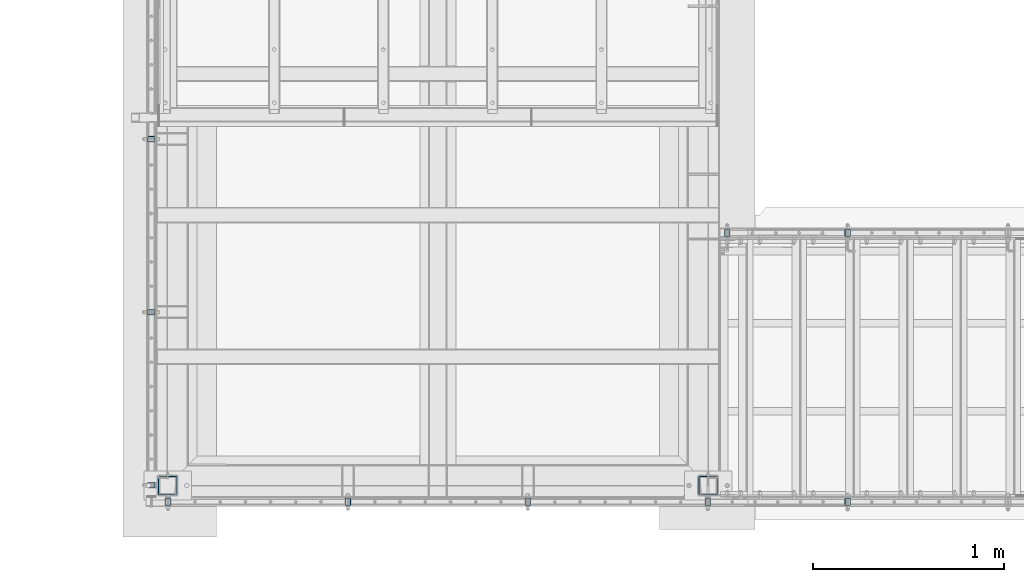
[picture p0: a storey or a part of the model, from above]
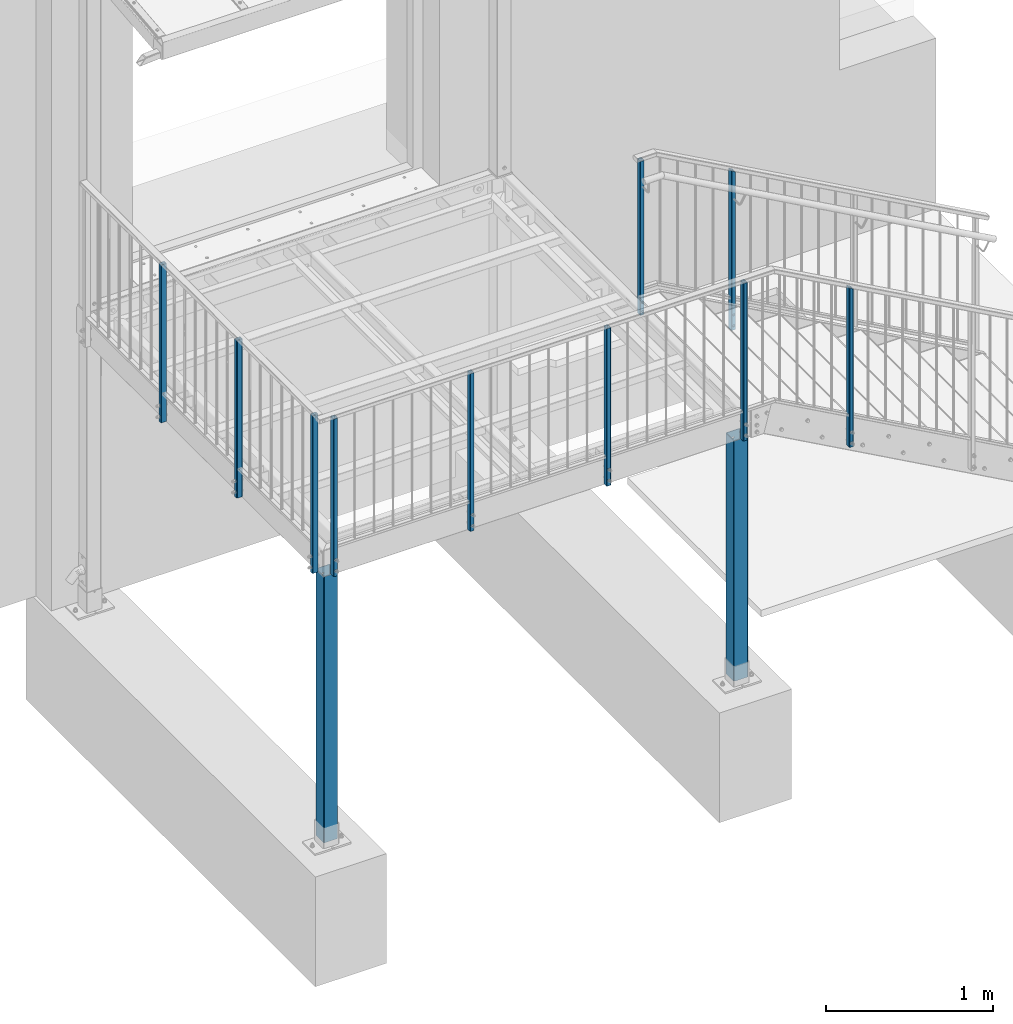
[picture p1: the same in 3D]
Properties of the parts of a building model (IFC2X3)

# File
Description: ViewDefinition[CoordinationView_V2.0]
File name: Einzelbalkon mit Zugangstreppe Bonn_ifc2x3.ifc
Time: 2026-07-13T14:27:18
Written by: IFC Toolkit 2.0.26.0
Made in: Advance Steel 2024

# IfcBuildingStorey, Default Storey
In: Struktur 1
Elevation: 0 mm

# IfcBeam: - (100)
In: Default Storey
Name | Description = Section | Material | SectionFamily
- | Q100X4 | S235JR | RHS_Sections_square_c nach DIN
- | Rinnenprofil 130x5 | S235JR | Usr Rinnenprofile | Pset_BeamCommon - Reference: 26; Span: 2920 mm; Slope: 0 deg; IsExternal: no; LoadBearing: no
9 x - | FL75X6 | S235JR | Flat nach DIN
6 x - | Gummistreifen 60x3 | Gummi | Usr Auflagergummi schwarz | Pset_BeamCommon - Reference: 5; Span: 200 mm; Slope: 0 deg; IsExternal: no; LoadBearing: no
6 x - | L 200x100x10 | Alu | Usr Auflagerwinkel Alu | Pset_BeamCommon - Reference: 10; Span: 60 mm; Slope: 0 deg; IsExternal: no; LoadBearing: no
3 x - | RHS80X60X4 | S235JR | RHS_Sections_rectang_c nach DIN
27 x - | FL40X5 | S235JR | Flat nach DIN
- | L60X40X5 | S235JR | Angle_uneq DIN18800-1 | Pset_BeamCommon - Reference: 19; Span: 1340 mm; Slope: 0 deg; IsExternal: no; LoadBearing: no
2 x - | C-Profil 217x30x4 | S235JR | Usr Treppenwangen trefor W
8 x - | R30X20X2 | S235JR | RHS_Sections_rectang_c nach DIN
- | R50X30X3 | S235JR | RHS_Sections_rectang_c nach DIN | Pset_BeamCommon - Reference: 23; Span: 3139.58 mm; Slope: 0 deg; IsExternal: no; LoadBearing: no
- | R50X30X3 | S235JR | RHS_Sections_rectang_c nach DIN
19 x - | FL80X6 | S235JR | Flat nach DIN
8 x - |  | S235JR | Pset_BeamCommon - Reference: 2; Span: 1340 mm; Slope: 0 deg; IsExternal: no; LoadBearing: no
3 x - | G 200x5 (Typ III) | S355JR | Usr G-Profile Typ III
- | G 200x5 (Typ III) | S355JR | Usr G-Profile Typ III | Pset_BeamCommon - Reference: 18; Span: 2940 mm; Slope: 0 deg; IsExternal: no; LoadBearing: no
- | Hutprofil 100x5 | S355JR | Usr Hutprofile
- | R50X30X3 | S235JR | RHS_Sections_rectang_c nach DIN | Pset_BeamCommon - Reference: 24; Span: 2820 mm; Slope: 0 deg; IsExternal: no; LoadBearing: no
- | RHS?42.4x2.6 | S235JR | RHS rund EN10210-2 1990

# IfcBeam: Girder (8)
In: Default Storey
Material: S235JR
Pset_BeamCommon - Slope: 0 deg; IsExternal: no; LoadBearing: no
ProfileProperties - SectionFamily: Pipe nach mannesmann
Name | Description = Section | Reference | Span (mm)
Girder | RO82.5x5 (Mannesmann) | 1 | 220
2 x Girder | RO70x5 (Mannesmann) | 7 | 160
Girder | RO82.5x5 (Mannesmann) | 6 | 220
2 x Girder | RO70x5 (Mannesmann) | 8 | 174.999
2 x Girder | RO82.5x5 (Mannesmann) | 3 | 220

# IfcBuildingElementProxy: - (160)
In: Default Storey
Material: Kein

# IfcColumn: - (100)
In: Default Storey
Name | Description = Section | Material | SectionFamily
2 x - | Q100X4 | S235JR | RHS_Sections_square_c nach DIN | Pset_ColumnCommon - Reference: 15; Slope: 0 deg; IsExternal: no; LoadBearing: no
- | Q100X4 | S235JR | RHS_Sections_square_c nach DIN | Pset_ColumnCommon - Reference: 21; Slope: 0 deg; IsExternal: no; LoadBearing: no
- | RO50x2.5 | A500 GR.C | RUS_R8732-78 | Pset_ColumnCommon - Reference: 22; Slope: 0 deg; IsExternal: no; LoadBearing: no
6 x - | Q90X4 | S235JR | RHS_Sections_square_c nach DIN
15 x - | R40X30X3 | S235JR | RHS_Sections_rectang_c nach DIN
2 x - | Q100X4 | S235JR | RHS_Sections_square_c nach DIN
2 x - | C-Profil 217x30x4 | S235JR | Usr Treppenwangen trefor W
69 x - | RD12 | S235JR | Round nach DIN
- | RHS?48.3x2 | S235JR | RHS rund EN10210-2 1990
- | Q100X4 | S235JR | RHS_Sections_square_c nach DIN | Pset_ColumnCommon - Reference: 20; Slope: 0 deg; IsExternal: no; LoadBearing: no

# IfcMechanicalFastener: - (94)
In: Default Storey
Name | NominalDiameter (mm) | NominalLength (mm)
6 x  | 8 | 20
24 x  | 6 | 40
4 x  | 12 | 120
2 x  | 16 | 40
2 x  | 16 | 140
31 x  | 12 | 40
2 x  | 12 | 130
17 x  | 12 | 70
 | 8 | 55
4 x  | 12 | 65
 | 12 | 80

# IfcMember: - (32)
In: Default Storey
Name | Description = Section | Material | SectionFamily | Reference | Span (mm) | Slope (deg) | IsExternal = LoadBearing
2 x - | Q100X4 | S235JR | RHS_Sections_square_c nach DIN
4 x - | Q60X3 | S235JR | RHS_Sections_square_c nach DIN
2 x - | FL20X8 | Alu | Flat nach DIN | 14 | 954.996 | 0 | no
- | Q50X4 | S235JR | RHS_Sections_square_c nach DIN
6 x - | Weichgummistreifen f?r Dachbelag 50x3 | S235JR | Usr Dachprofile | 11 | 904.996 | 0 | no
6 x - | Abdeckleiste f?r Dachbelag 50x5 | S235JR | Usr Dachprofile | 4 | 954.996 | 0 | no
- | C-Profil 217x30x4 | S235JR | Usr Treppenwangen trefor W | 16 | 2564.55 | 0 | no
- | C-Profil 217x30x4 | S235JR | Usr Treppenwangen trefor W | 17 | 2564.55 | 0 | no
- | R50X30X3 | S235JR | RHS_Sections_rectang_c nach DIN
6 x - | R30X20X2 | S235JR | RHS_Sections_rectang_c nach DIN
- | R50X30X3 | S235JR | RHS_Sections_rectang_c nach DIN | 25 | 2621.54 | 0 | no
- | RHS?42.4x2.6 | S235JR | RHS rund EN10210-2 1990

# IfcPlate: - (73)
In: Default Storey
Description: -
Pset_PlateCommon - IsExternal: no; LoadBearing: no
Name | Material | Reference
2 x - | S235JR 10 mm | 452
8 x - | S235JR 6 mm | 451
5 x - | Glas 8.76 mm | 38
- | S235JR 5 mm | 459
2 x - | S235JR 5 mm | 457
- | S235JR 5 mm | 460
8 x - | Mineralit 35 mm | 32
16 x - | S235JR 5 mm | 450
- | Alu 5 mm | 47
- | Thermostop 6 mm | 9
- | S235JR 10 mm | 400
2 x - | S355JR 15 mm | 409
4 x - | S355JR 15 mm | 408
- | S355JR 15 mm | 401
- | Thermostop 6 mm | 13
- | S355JR 15 mm | 406
2 x - | Thermostop 6 mm | 12
2 x - | S355JR 15 mm | 410
2 x - | S355JR 15 mm | 405
- | Mineralit 35 mm | 46
2 x - | S235JR 5 mm | 456
2 x - | S235JR 10 mm | 455
2 x - | S235JR 10 mm | 454
2 x - | S235JR 10 mm | 453
2 x - | Mineralit 35 mm | 44
- | S235JR 3 mm | 458

# IfcSlab: - (6)
In: Default Storey
Description: -
Pset_SlabCommon - Reference: nicht definiert; IsExternal: no; LoadBearing: no; Combustible: no; Compartmentation: no; PitchAngle: 0 deg
Name | Material
3 x - | C25/30 800 mm
- | C25/30 170 mm
- | C25/30 240 mm
- | C25/30 1872 mm

# IfcSlab: Gokoba_Estrich (3)
In: Default Storey
Description: -
Pset_SlabCommon - Reference: nicht definiert; IsExternal: no; LoadBearing: no; Combustible: no; Compartmentation: no; PitchAngle: 0 deg
Name | Material
Gokoba_Estrich | C25/30 70 mm
Gokoba_Estrich | Estrich 155 mm
Gokoba_Estrich | C25/30 50 mm

# IfcWall: Gokoba_D?mmung (2)
In: Default Storey
Description: -
Pset_WallCommon - Reference: nicht definiert; Combustible: no; IsExternal: no; ExtendToStructure: no; LoadBearing: no; Compartmentation: no
Name | Material
Gokoba_D?mmung | C25/30 450 mm
Gokoba_D?mmung | C25/30 180 mm

# IfcWall: Gokoba_Mauerwerk
In: Default Storey
Description: -; Material: Mauer 1000 mm
Pset_WallCommon - Reference: nicht definiert; Combustible: no; IsExternal: no; ExtendToStructure: no; LoadBearing: no; Compartmentation: no
